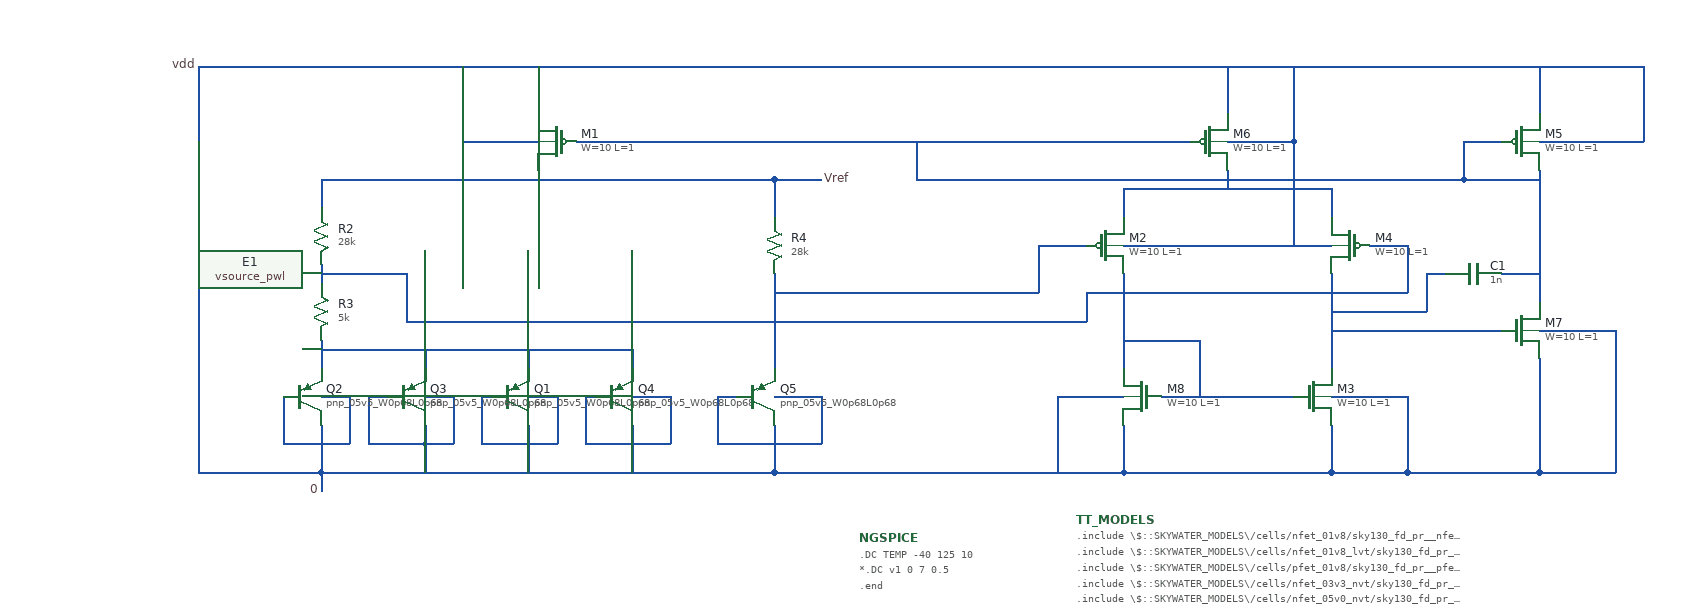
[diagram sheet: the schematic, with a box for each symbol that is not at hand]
v {xschem version=2.9.9 file_version=1.2 }
G {}
K {}
V {}
S {}
E {}
N 1910 -1480 1910 -1430 { lab=0}
N 1910 -1430 1910 -1410 { lab=0}
N 1910 -1430 1980 -1430 { lab=0}
N 2220 -1430 2320 -1430 { lab=0}
N 2320 -1430 2390 -1430 { lab=0}
N 2100 -1430 2220 -1430 { lab=0}
N 2040 -1430 2100 -1430 { lab=0}
N 2390 -1430 2500 -1430 { lab=0}
N 2500 -1430 2570 -1430 { lab=0}
N 2570 -1430 2640 -1430 { lab=0}
N 2800 -1510 2940 -1510 { lab=#net1}
N 2760 -1610 2760 -1540 { lab=#net1}
N 2980 -1610 2980 -1540 { lab=#net2}
N 2840 -1570 2840 -1510 { lab=#net1}
N 2760 -1570 2840 -1570 { lab=#net1}
N 2980 -1480 2980 -1430 { lab=0}
N 2760 -1430 2980 -1430 { lab=0}
N 2760 -1480 2760 -1430 { lab=0}
N 2980 -1640 2980 -1610 { lab=#net2}
N 2760 -1640 2760 -1610 { lab=#net1}
N 2980 -1730 2980 -1700 { lab=#net3}
N 2760 -1730 2980 -1730 { lab=#net3}
N 2760 -1730 2760 -1700 { lab=#net3}
N 2870 -1750 2870 -1730 { lab=#net3}
N 2760 -1670 2810 -1670 { lab=vdd}
N 2810 -1670 2980 -1670 { lab=vdd}
N 2980 -1510 3020 -1510 { lab=0}
N 2640 -1430 2760 -1430 { lab=0}
N 2690 -1510 2760 -1510 { lab=0}
N 2690 -1510 2690 -1430 { lab=0}
N 3020 -1510 3060 -1510 { lab=0}
N 3060 -1510 3060 -1440 { lab=0}
N 3060 -1440 3060 -1430 { lab=0}
N 2980 -1430 3060 -1430 { lab=0}
N 2980 -1580 3160 -1580 { lab=#net2}
N 1910 -1650 1910 -1630 { lab=#net4}
N 1910 -1740 2200 -1740 { lab=Vref}
N 3200 -1550 3200 -1430 { lab=0}
N 3060 -1430 3200 -1430 { lab=0}
N 3280 -1580 3280 -1430 { lab=0}
N 3200 -1750 3200 -1610 { lab=#net5}
N 3200 -1780 3310 -1780 { lab=vdd}
N 3310 -1860 3310 -1780 { lab=vdd}
N 2040 -1860 3310 -1860 { lab=vdd}
N 3200 -1860 3200 -1810 { lab=vdd}
N 2870 -1860 2870 -1810 { lab=vdd}
N 3060 -1670 3060 -1620 { lab=#net4}
N 3020 -1670 3060 -1670 { lab=#net4}
N 2670 -1670 2720 -1670 { lab=#net6}
N 1780 -1650 1780 -1430 { lab=0}
N 2390 -1740 2440 -1740 { lab=Vref}
N 2980 -1600 3080 -1600 { lab=#net2}
N 3080 -1640 3080 -1600 { lab=#net2}
N 3080 -1640 3100 -1640 { lab=#net2}
N 3160 -1640 3200 -1640 { lab=#net5}
N 1980 -1430 2040 -1430 { lab=0}
N 2870 -1780 2940 -1780 { lab=vdd}
N 2940 -1780 2940 -1670 { lab=vdd}
N 2940 -1860 2940 -1780 { lab=vdd}
N 3120 -1780 3170 -1780 { lab=#net5}
N 2540 -1740 3120 -1740 { lab=#net5}
N 1910 -1740 1910 -1730 { lab=Vref}
N 1910 -1570 1910 -1540 { lab=#net7}
N 1910 -1730 1910 -1710 { lab=Vref}
N 2390 -1640 2390 -1600 { lab=#net6}
N 2390 -1740 2390 -1700 { lab=Vref}
N 1910 -1510 1940 -1510 { lab=0}
N 1940 -1510 1940 -1460 { lab=0}
N 1910 -1460 1940 -1460 { lab=0}
N 1870 -1510 1870 -1460 { lab=0}
N 1870 -1460 1910 -1460 { lab=0}
N 1960 -1510 1980 -1510 { lab=0}
N 1960 -1510 1960 -1460 { lab=0}
N 1960 -1460 2020 -1460 { lab=0}
N 2020 -1510 2050 -1510 { lab=0}
N 2050 -1510 2050 -1460 { lab=0}
N 2020 -1460 2050 -1460 { lab=0}
N 2020 -1480 2020 -1460 { lab=0}
N 2020 -1460 2020 -1430 { lab=0}
N 2080 -1510 2090 -1510 { lab=0}
N 2080 -1510 2080 -1460 { lab=0}
N 2080 -1460 2160 -1460 { lab=0}
N 2160 -1510 2160 -1460 { lab=0}
N 2130 -1510 2160 -1510 { lab=0}
N 2130 -1480 2130 -1460 { lab=0}
N 2130 -1460 2130 -1430 { lab=0}
N 2190 -1510 2200 -1510 { lab=0}
N 2190 -1510 2190 -1460 { lab=0}
N 2190 -1460 2280 -1460 { lab=0}
N 2280 -1510 2280 -1460 { lab=0}
N 2240 -1510 2280 -1510 { lab=0}
N 2240 -1480 2240 -1460 { lab=0}
N 2240 -1460 2240 -1430 { lab=0}
N 2200 -1740 2390 -1740 { lab=Vref}
N 2390 -1600 2390 -1540 { lab=#net6}
N 2330 -1510 2350 -1510 { lab=0}
N 2330 -1510 2330 -1460 { lab=0}
N 2330 -1460 2440 -1460 { lab=0}
N 2440 -1510 2440 -1460 { lab=0}
N 2390 -1510 2440 -1510 { lab=0}
N 2390 -1480 2390 -1460 { lab=0}
N 2390 -1460 2390 -1430 { lab=0}
N 2240 -1560 2240 -1540 { lab=#net7}
N 1910 -1560 2240 -1560 { lab=#net7}
N 2020 -1560 2020 -1540 { lab=#net7}
N 2130 -1560 2130 -1540 { lab=#net7}
N 2670 -1670 2670 -1620 { lab=#net6}
N 2390 -1620 2670 -1620 { lab=#net6}
N 2720 -1620 3060 -1620 { lab=#net4}
N 2720 -1620 2720 -1590 { lab=#net4}
N 2000 -1590 2720 -1590 { lab=#net4}
N 2000 -1640 2000 -1590 { lab=#net4}
N 1910 -1640 2000 -1640 { lab=#net4}
N 2140 -1750 2140 -1740 { lab=Vref}
N 2140 -1860 2140 -1810 { lab=vdd}
N 2180 -1780 2830 -1780 { lab=#net5}
N 3120 -1740 3200 -1740 { lab=#net5}
N 3120 -1780 3120 -1740 { lab=#net5}
N 3200 -1580 3280 -1580 { lab=0}
N 3200 -1430 3280 -1430 { lab=0}
N 2060 -1780 2140 -1780 { lab=vdd}
N 2060 -1860 2060 -1780 { lab=vdd}
N 2540 -1780 2540 -1740 { lab=#net5}
N 1910 -1860 2040 -1860 { lab=vdd}
N 1780 -1860 1910 -1860 { lab=vdd}
N 1780 -1430 1910 -1430 { lab=0}
N 1780 -1690 1780 -1650 { lab=0}
N 1780 -1720 1780 -1690 { lab=0}
N 1780 -1860 1780 -1780 { lab=vdd}
C {/home/eslam/xschem_git/xschem_library/devices/lab_pin.sym} 1910 -1410 0 0 {name=l1 sig_type=std_logic lab=0}
C {sky130_fd_pr/pnp_05v5.sym} 1890 -1510 0 0 {name=Q2
model=pnp_05v5_W0p68L0p68
spiceprefix=X
}
C {sky130_fd_pr/pnp_05v5.sym} 2110 -1510 0 0 {name=Q1
model=pnp_05v5_W0p68L0p68
spiceprefix=X
}
C {sky130_fd_pr/pnp_05v5.sym} 2000 -1510 0 0 {name=Q3
model=pnp_05v5_W0p68L0p68
spiceprefix=X
}
C {sky130_fd_pr/pnp_05v5.sym} 2220 -1510 0 0 {name=Q4
model=pnp_05v5_W0p68L0p68
spiceprefix=X
}
C {devices/lab_pin.sym} 2440 -1740 0 1 {name=l4 sig_type=std_logic lab=Vref}
C {devices/capa.sym} 3130 -1640 3 0 {name=C1
m=1
value=1n
footprint=1206
device="ceramic capacitor"}
C {devices/code.sym} 2710 -1380 0 0 {name=TT_MODELS
only_toplevel=true
format="tcleval( @value )"
value="
.include \\\\$::SKYWATER_MODELS\\\\/cells/nfet_01v8/sky130_fd_pr__nfet_01v8__tt.corner.spice
.include \\\\$::SKYWATER_MODELS\\\\/cells/nfet_01v8_lvt/sky130_fd_pr__nfet_01v8_lvt__tt.corner.spice
.include \\\\$::SKYWATER_MODELS\\\\/cells/pfet_01v8/sky130_fd_pr__pfet_01v8__tt.corner.spice
.include \\\\$::SKYWATER_MODELS\\\\/cells/nfet_03v3_nvt/sky130_fd_pr__nfet_03v3_nvt__tt.corner.spice
.include \\\\$::SKYWATER_MODELS\\\\/cells/nfet_05v0_nvt/sky130_fd_pr__nfet_05v0_nvt__tt.corner.spice
.include \\\\$::SKYWATER_MODELS\\\\/cells/esd_nfet_01v8/sky130_fd_pr__esd_nfet_01v8__tt.corner.spice
.include \\\\$::SKYWATER_MODELS\\\\/cells/pfet_01v8_lvt/sky130_fd_pr__pfet_01v8_lvt__tt.corner.spice
.include \\\\$::SKYWATER_MODELS\\\\/cells/pfet_01v8_hvt/sky130_fd_pr__pfet_01v8_hvt__tt.corner.spice
.include \\\\$::SKYWATER_MODELS\\\\/cells/esd_pfet_g5v0d10v5/sky130_fd_pr__esd_pfet_g5v0d10v5__tt.corner.spice
.include \\\\$::SKYWATER_MODELS\\\\/cells/pfet_g5v0d10v5/sky130_fd_pr__pfet_g5v0d10v5__tt.corner.spice
.include \\\\$::SKYWATER_MODELS\\\\/cells/pfet_g5v0d16v0/sky130_fd_pr__pfet_g5v0d16v0__tt.corner.spice
.include \\\\$::SKYWATER_MODELS\\\\/cells/nfet_g5v0d10v5/sky130_fd_pr__nfet_g5v0d10v5__tt.corner.spice
.include \\\\$::SKYWATER_MODELS\\\\/cells/nfet_g5v0d16v0/sky130_fd_pr__nfet_g5v0d16v0__tt_discrete.corner.spice
.include \\\\$::SKYWATER_MODELS\\\\/cells/esd_nfet_g5v0d10v5/sky130_fd_pr__esd_nfet_g5v0d10v5__tt.corner.spice
.include \\\\$::SKYWATER_MODELS\\\\/models/corners/tt/nonfet.spice
* Mismatch parameters
.include \\\\$::SKYWATER_MODELS\\\\/cells/nfet_01v8/sky130_fd_pr__nfet_01v8__mismatch.corner.spice
.include \\\\$::SKYWATER_MODELS\\\\/cells/pfet_01v8/sky130_fd_pr__pfet_01v8__mismatch.corner.spice
.include \\\\$::SKYWATER_MODELS\\\\/cells/nfet_01v8_lvt/sky130_fd_pr__nfet_01v8_lvt__mismatch.corner.spice
.include \\\\$::SKYWATER_MODELS\\\\/cells/pfet_01v8_lvt/sky130_fd_pr__pfet_01v8_lvt__mismatch.corner.spice
.include \\\\$::SKYWATER_MODELS\\\\/cells/pfet_01v8_hvt/sky130_fd_pr__pfet_01v8_hvt__mismatch.corner.spice
.include \\\\$::SKYWATER_MODELS\\\\/cells/nfet_g5v0d10v5/sky130_fd_pr__nfet_g5v0d10v5__mismatch.corner.spice
.include \\\\$::SKYWATER_MODELS\\\\/cells/pfet_g5v0d10v5/sky130_fd_pr__pfet_g5v0d10v5__mismatch.corner.spice
.include \\\\$::SKYWATER_MODELS\\\\/cells/nfet_05v0_nvt/sky130_fd_pr__nfet_05v0_nvt__mismatch.corner.spice
.include \\\\$::SKYWATER_MODELS\\\\/cells/nfet_03v3_nvt/sky130_fd_pr__nfet_03v3_nvt__mismatch.corner.spice
* Resistor\\\\$::SKYWATER_MODELS\\\\/Capacitor
.include \\\\$::SKYWATER_MODELS\\\\/models/r+c/res_typical__cap_typical.spice
.include \\\\$::SKYWATER_MODELS\\\\/models/r+c/res_typical__cap_typical__lin.spice
* Special cells
.include \\\\$::SKYWATER_MODELS\\\\/models/corners/tt/specialized_cells.spice
* All models
.include \\\\$::SKYWATER_MODELS\\\\/models/all.spice
* Corner
.include \\\\$::SKYWATER_MODELS\\\\/models/corners/tt/rf.spice
"}
C {devices/code_shown.sym} 2480 -1360 0 0 {name=NGSPICE
only_toplevel=true
value="
.DC TEMP -40 125 10
*.DC v1 0 7 0.5
.end
" }
C {sky130_fd_pr/pnp_05v5.sym} 2370 -1510 0 0 {name=Q5
model=pnp_05v5_W0p68L0p68
spiceprefix=X
}
C {devices/lab_pin.sym} 1780 -1860 0 0 {name=l2 sig_type=std_logic lab=vdd}
C {devices/res.sym} 1910 -1680 0 0 {name=R2
value=28k
footprint=1206
device=resistor
m=1}
C {devices/res.sym} 1910 -1600 0 0 {name=R3
value=5k
footprint=1206
device=resistor
m=1}
C {devices/res.sym} 2390 -1670 0 0 {name=R4
value=28k
footprint=1206
device=resistor
m=1}
C {sky130_fd_pr/pfet_g5v0d10v5.sym} 2740 -1670 0 0 {name=M2
L=1
W=10
nf=1
mult=1
ad="'int((nf+1)/2) * W/nf * 0.29'" 
pd="'2*int((nf+1)/2) * (W/nf + 0.29)'"
as="'int((nf+2)/2) * W/nf * 0.29'" 
ps="'2*int((nf+2)/2) * (W/nf + 0.29)'"
nrd="'0.29 / W'" nrs="'0.29 / W'"
sa=0 sb=0 sd=0
model=pfet_g5v0d10v5
spiceprefix=X
}
C {sky130_fd_pr/pfet_g5v0d10v5.sym} 3000 -1670 0 1 {name=M4
L=1
W=10
nf=1
mult=1
ad="'int((nf+1)/2) * W/nf * 0.29'" 
pd="'2*int((nf+1)/2) * (W/nf + 0.29)'"
as="'int((nf+2)/2) * W/nf * 0.29'" 
ps="'2*int((nf+2)/2) * (W/nf + 0.29)'"
nrd="'0.29 / W'" nrs="'0.29 / W'"
sa=0 sb=0 sd=0
model=pfet_g5v0d10v5
spiceprefix=X
}
C {sky130_fd_pr/pfet_g5v0d10v5.sym} 3180 -1780 0 0 {name=M5
L=1
W=10
nf=1
mult=1
ad="'int((nf+1)/2) * W/nf * 0.29'" 
pd="'2*int((nf+1)/2) * (W/nf + 0.29)'"
as="'int((nf+2)/2) * W/nf * 0.29'" 
ps="'2*int((nf+2)/2) * (W/nf + 0.29)'"
nrd="'0.29 / W'" nrs="'0.29 / W'"
sa=0 sb=0 sd=0
model=pfet_g5v0d10v5
spiceprefix=X
}
C {sky130_fd_pr/pfet_g5v0d10v5.sym} 2850 -1780 0 0 {name=M6
L=1
W=10
nf=1
mult=1
ad="'int((nf+1)/2) * W/nf * 0.29'" 
pd="'2*int((nf+1)/2) * (W/nf + 0.29)'"
as="'int((nf+2)/2) * W/nf * 0.29'" 
ps="'2*int((nf+2)/2) * (W/nf + 0.29)'"
nrd="'0.29 / W'" nrs="'0.29 / W'"
sa=0 sb=0 sd=0
model=pfet_g5v0d10v5
spiceprefix=X
}
C {sky130_fd_pr/pfet_g5v0d10v5.sym} 2160 -1780 0 1 {name=M1
L=1
W=10
nf=1
mult=1
ad="'int((nf+1)/2) * W/nf * 0.29'" 
pd="'2*int((nf+1)/2) * (W/nf + 0.29)'"
as="'int((nf+2)/2) * W/nf * 0.29'" 
ps="'2*int((nf+2)/2) * (W/nf + 0.29)'"
nrd="'0.29 / W'" nrs="'0.29 / W'"
sa=0 sb=0 sd=0
model=pfet_g5v0d10v5
spiceprefix=X
}
C {sky130_fd_pr/nfet_g5v0d10v5.sym} 2960 -1510 0 0 {name=M3
L=1
W=10
nf=1
mult=1
ad="'int((nf+1)/2) * W/nf * 0.29'" 
pd="'2*int((nf+1)/2) * (W/nf + 0.29)'"
as="'int((nf+2)/2) * W/nf * 0.29'" 
ps="'2*int((nf+2)/2) * (W/nf + 0.29)'"
nrd="'0.29 / W'" nrs="'0.29 / W'"
sa=0 sb=0 sd=0
model=nfet_g5v0d10v5
spiceprefix=X
}
C {sky130_fd_pr/nfet_g5v0d10v5.sym} 3180 -1580 0 0 {name=M7
L=1
W=10
nf=1
mult=500
ad="'int((nf+1)/2) * W/nf * 0.29'" 
pd="'2*int((nf+1)/2) * (W/nf + 0.29)'"
as="'int((nf+2)/2) * W/nf * 0.29'" 
ps="'2*int((nf+2)/2) * (W/nf + 0.29)'"
nrd="'0.29 / W'" nrs="'0.29 / W'"
sa=0 sb=0 sd=0
model=nfet_g5v0d10v5
spiceprefix=X
}
C {sky130_fd_pr/nfet_g5v0d10v5.sym} 2780 -1510 0 1 {name=M8
L=1
W=10
nf=1
mult=1
ad="'int((nf+1)/2) * W/nf * 0.29'" 
pd="'2*int((nf+1)/2) * (W/nf + 0.29)'"
as="'int((nf+2)/2) * W/nf * 0.29'" 
ps="'2*int((nf+2)/2) * (W/nf + 0.29)'"
nrd="'0.29 / W'" nrs="'0.29 / W'"
sa=0 sb=0 sd=0
model=nfet_g5v0d10v5
spiceprefix=X
}
C {devices/vsource_pwl.sym} 1660 -1520 0 0 {name=E1 TABLE="1 0 2 3"}
